VERSION 5.7 ;
  NOWIREEXTENSIONATPIN ON ;
  DIVIDERCHAR "/" ;
  BUSBITCHARS "[]" ;
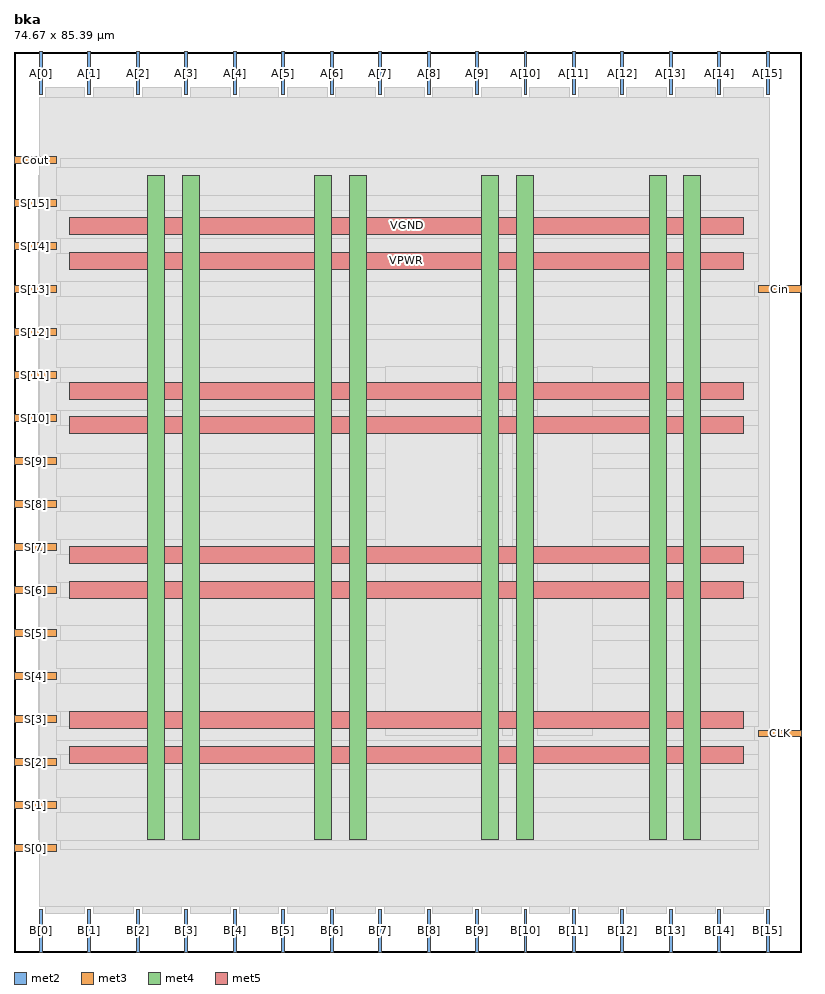
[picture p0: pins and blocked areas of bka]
MACRO bka
  CLASS BLOCK ;
  FOREIGN bka ;
  ORIGIN 0.000 0.000 ;
  SIZE 74.670 BY 85.390 ;
  PIN A[0]
    DIRECTION INPUT ;
    USE SIGNAL ;
    ANTENNAGATEAREA 0.196500 ;
    PORT
      LAYER met2 ;
        RECT 2.390 81.390 2.670 85.390 ;
    END
  END A[0]
  PIN A[10]
    DIRECTION INPUT ;
    USE SIGNAL ;
    ANTENNAGATEAREA 0.196500 ;
    PORT
      LAYER met2 ;
        RECT 48.390 81.390 48.670 85.390 ;
    END
  END A[10]
  PIN A[11]
    DIRECTION INPUT ;
    USE SIGNAL ;
    ANTENNAGATEAREA 0.196500 ;
    PORT
      LAYER met2 ;
        RECT 52.990 81.390 53.270 85.390 ;
    END
  END A[11]
  PIN A[12]
    DIRECTION INPUT ;
    USE SIGNAL ;
    ANTENNAGATEAREA 0.196500 ;
    PORT
      LAYER met2 ;
        RECT 57.590 81.390 57.870 85.390 ;
    END
  END A[12]
  PIN A[13]
    DIRECTION INPUT ;
    USE SIGNAL ;
    ANTENNAGATEAREA 0.196500 ;
    PORT
      LAYER met2 ;
        RECT 62.190 81.390 62.470 85.390 ;
    END
  END A[13]
  PIN A[14]
    DIRECTION INPUT ;
    USE SIGNAL ;
    ANTENNAGATEAREA 0.196500 ;
    PORT
      LAYER met2 ;
        RECT 66.790 81.390 67.070 85.390 ;
    END
  END A[14]
  PIN A[15]
    DIRECTION INPUT ;
    USE SIGNAL ;
    ANTENNAGATEAREA 0.196500 ;
    PORT
      LAYER met2 ;
        RECT 71.390 81.390 71.670 85.390 ;
    END
  END A[15]
  PIN A[1]
    DIRECTION INPUT ;
    USE SIGNAL ;
    ANTENNAGATEAREA 0.196500 ;
    PORT
      LAYER met2 ;
        RECT 6.990 81.390 7.270 85.390 ;
    END
  END A[1]
  PIN A[2]
    DIRECTION INPUT ;
    USE SIGNAL ;
    ANTENNAGATEAREA 0.196500 ;
    PORT
      LAYER met2 ;
        RECT 11.590 81.390 11.870 85.390 ;
    END
  END A[2]
  PIN A[3]
    DIRECTION INPUT ;
    USE SIGNAL ;
    ANTENNAGATEAREA 0.196500 ;
    PORT
      LAYER met2 ;
        RECT 16.190 81.390 16.470 85.390 ;
    END
  END A[3]
  PIN A[4]
    DIRECTION INPUT ;
    USE SIGNAL ;
    ANTENNAGATEAREA 0.196500 ;
    PORT
      LAYER met2 ;
        RECT 20.790 81.390 21.070 85.390 ;
    END
  END A[4]
  PIN A[5]
    DIRECTION INPUT ;
    USE SIGNAL ;
    ANTENNAGATEAREA 0.196500 ;
    PORT
      LAYER met2 ;
        RECT 25.390 81.390 25.670 85.390 ;
    END
  END A[5]
  PIN A[6]
    DIRECTION INPUT ;
    USE SIGNAL ;
    ANTENNAGATEAREA 0.196500 ;
    PORT
      LAYER met2 ;
        RECT 29.990 81.390 30.270 85.390 ;
    END
  END A[6]
  PIN A[7]
    DIRECTION INPUT ;
    USE SIGNAL ;
    ANTENNAGATEAREA 0.196500 ;
    PORT
      LAYER met2 ;
        RECT 34.590 81.390 34.870 85.390 ;
    END
  END A[7]
  PIN A[8]
    DIRECTION INPUT ;
    USE SIGNAL ;
    ANTENNAGATEAREA 0.196500 ;
    PORT
      LAYER met2 ;
        RECT 39.190 81.390 39.470 85.390 ;
    END
  END A[8]
  PIN A[9]
    DIRECTION INPUT ;
    USE SIGNAL ;
    ANTENNAGATEAREA 0.196500 ;
    PORT
      LAYER met2 ;
        RECT 43.790 81.390 44.070 85.390 ;
    END
  END A[9]
  PIN B[0]
    DIRECTION INPUT ;
    USE SIGNAL ;
    ANTENNAGATEAREA 0.196500 ;
    PORT
      LAYER met2 ;
        RECT 2.390 0.000 2.670 4.000 ;
    END
  END B[0]
  PIN B[10]
    DIRECTION INPUT ;
    USE SIGNAL ;
    ANTENNAGATEAREA 0.196500 ;
    PORT
      LAYER met2 ;
        RECT 48.390 0.000 48.670 4.000 ;
    END
  END B[10]
  PIN B[11]
    DIRECTION INPUT ;
    USE SIGNAL ;
    ANTENNAGATEAREA 0.196500 ;
    PORT
      LAYER met2 ;
        RECT 52.990 0.000 53.270 4.000 ;
    END
  END B[11]
  PIN B[12]
    DIRECTION INPUT ;
    USE SIGNAL ;
    ANTENNAGATEAREA 0.196500 ;
    PORT
      LAYER met2 ;
        RECT 57.590 0.000 57.870 4.000 ;
    END
  END B[12]
  PIN B[13]
    DIRECTION INPUT ;
    USE SIGNAL ;
    ANTENNAGATEAREA 0.196500 ;
    PORT
      LAYER met2 ;
        RECT 62.190 0.000 62.470 4.000 ;
    END
  END B[13]
  PIN B[14]
    DIRECTION INPUT ;
    USE SIGNAL ;
    ANTENNAGATEAREA 0.196500 ;
    PORT
      LAYER met2 ;
        RECT 66.790 0.000 67.070 4.000 ;
    END
  END B[14]
  PIN B[15]
    DIRECTION INPUT ;
    USE SIGNAL ;
    ANTENNAGATEAREA 0.196500 ;
    PORT
      LAYER met2 ;
        RECT 71.390 0.000 71.670 4.000 ;
    END
  END B[15]
  PIN B[1]
    DIRECTION INPUT ;
    USE SIGNAL ;
    ANTENNAGATEAREA 0.196500 ;
    PORT
      LAYER met2 ;
        RECT 6.990 0.000 7.270 4.000 ;
    END
  END B[1]
  PIN B[2]
    DIRECTION INPUT ;
    USE SIGNAL ;
    ANTENNAGATEAREA 0.196500 ;
    PORT
      LAYER met2 ;
        RECT 11.590 0.000 11.870 4.000 ;
    END
  END B[2]
  PIN B[3]
    DIRECTION INPUT ;
    USE SIGNAL ;
    ANTENNAGATEAREA 0.196500 ;
    PORT
      LAYER met2 ;
        RECT 16.190 0.000 16.470 4.000 ;
    END
  END B[3]
  PIN B[4]
    DIRECTION INPUT ;
    USE SIGNAL ;
    ANTENNAGATEAREA 0.196500 ;
    PORT
      LAYER met2 ;
        RECT 20.790 0.000 21.070 4.000 ;
    END
  END B[4]
  PIN B[5]
    DIRECTION INPUT ;
    USE SIGNAL ;
    ANTENNAGATEAREA 0.196500 ;
    PORT
      LAYER met2 ;
        RECT 25.390 0.000 25.670 4.000 ;
    END
  END B[5]
  PIN B[6]
    DIRECTION INPUT ;
    USE SIGNAL ;
    ANTENNAGATEAREA 0.196500 ;
    PORT
      LAYER met2 ;
        RECT 29.990 0.000 30.270 4.000 ;
    END
  END B[6]
  PIN B[7]
    DIRECTION INPUT ;
    USE SIGNAL ;
    ANTENNAGATEAREA 0.196500 ;
    PORT
      LAYER met2 ;
        RECT 34.590 0.000 34.870 4.000 ;
    END
  END B[7]
  PIN B[8]
    DIRECTION INPUT ;
    USE SIGNAL ;
    ANTENNAGATEAREA 0.196500 ;
    PORT
      LAYER met2 ;
        RECT 39.190 0.000 39.470 4.000 ;
    END
  END B[8]
  PIN B[9]
    DIRECTION INPUT ;
    USE SIGNAL ;
    ANTENNAGATEAREA 0.196500 ;
    PORT
      LAYER met2 ;
        RECT 43.790 0.000 44.070 4.000 ;
    END
  END B[9]
  PIN CLK
    DIRECTION INPUT ;
    USE SIGNAL ;
    ANTENNAGATEAREA 0.852000 ;
    PORT
      LAYER met3 ;
        RECT 70.670 20.440 74.670 21.040 ;
    END
  END CLK
  PIN Cin
    DIRECTION INPUT ;
    USE SIGNAL ;
    ANTENNAGATEAREA 0.196500 ;
    PORT
      LAYER met3 ;
        RECT 70.670 62.600 74.670 63.200 ;
    END
  END Cin
  PIN Cout
    DIRECTION OUTPUT ;
    USE SIGNAL ;
    ANTENNADIFFAREA 0.340600 ;
    PORT
      LAYER met3 ;
        RECT 0.000 74.840 4.000 75.440 ;
    END
  END Cout
  PIN S[0]
    DIRECTION OUTPUT ;
    USE SIGNAL ;
    ANTENNADIFFAREA 0.340600 ;
    PORT
      LAYER met3 ;
        RECT 0.000 9.560 4.000 10.160 ;
    END
  END S[0]
  PIN S[10]
    DIRECTION OUTPUT ;
    USE SIGNAL ;
    ANTENNADIFFAREA 0.340600 ;
    PORT
      LAYER met3 ;
        RECT 0.000 50.360 4.000 50.960 ;
    END
  END S[10]
  PIN S[11]
    DIRECTION OUTPUT ;
    USE SIGNAL ;
    ANTENNADIFFAREA 0.340600 ;
    PORT
      LAYER met3 ;
        RECT 0.000 54.440 4.000 55.040 ;
    END
  END S[11]
  PIN S[12]
    DIRECTION OUTPUT ;
    USE SIGNAL ;
    ANTENNADIFFAREA 0.340600 ;
    PORT
      LAYER met3 ;
        RECT 0.000 58.520 4.000 59.120 ;
    END
  END S[12]
  PIN S[13]
    DIRECTION OUTPUT ;
    USE SIGNAL ;
    ANTENNADIFFAREA 0.340600 ;
    PORT
      LAYER met3 ;
        RECT 0.000 62.600 4.000 63.200 ;
    END
  END S[13]
  PIN S[14]
    DIRECTION OUTPUT ;
    USE SIGNAL ;
    ANTENNADIFFAREA 0.340600 ;
    PORT
      LAYER met3 ;
        RECT 0.000 66.680 4.000 67.280 ;
    END
  END S[14]
  PIN S[15]
    DIRECTION OUTPUT ;
    USE SIGNAL ;
    ANTENNADIFFAREA 0.340600 ;
    PORT
      LAYER met3 ;
        RECT 0.000 70.760 4.000 71.360 ;
    END
  END S[15]
  PIN S[1]
    DIRECTION OUTPUT ;
    USE SIGNAL ;
    ANTENNADIFFAREA 0.340600 ;
    PORT
      LAYER met3 ;
        RECT 0.000 13.640 4.000 14.240 ;
    END
  END S[1]
  PIN S[2]
    DIRECTION OUTPUT ;
    USE SIGNAL ;
    ANTENNADIFFAREA 0.340600 ;
    PORT
      LAYER met3 ;
        RECT 0.000 17.720 4.000 18.320 ;
    END
  END S[2]
  PIN S[3]
    DIRECTION OUTPUT ;
    USE SIGNAL ;
    ANTENNADIFFAREA 0.340600 ;
    PORT
      LAYER met3 ;
        RECT 0.000 21.800 4.000 22.400 ;
    END
  END S[3]
  PIN S[4]
    DIRECTION OUTPUT ;
    USE SIGNAL ;
    ANTENNADIFFAREA 0.340600 ;
    PORT
      LAYER met3 ;
        RECT 0.000 25.880 4.000 26.480 ;
    END
  END S[4]
  PIN S[5]
    DIRECTION OUTPUT ;
    USE SIGNAL ;
    ANTENNADIFFAREA 0.340600 ;
    PORT
      LAYER met3 ;
        RECT 0.000 29.960 4.000 30.560 ;
    END
  END S[5]
  PIN S[6]
    DIRECTION OUTPUT ;
    USE SIGNAL ;
    ANTENNADIFFAREA 0.340600 ;
    PORT
      LAYER met3 ;
        RECT 0.000 34.040 4.000 34.640 ;
    END
  END S[6]
  PIN S[7]
    DIRECTION OUTPUT ;
    USE SIGNAL ;
    ANTENNADIFFAREA 0.340600 ;
    PORT
      LAYER met3 ;
        RECT 0.000 38.120 4.000 38.720 ;
    END
  END S[7]
  PIN S[8]
    DIRECTION OUTPUT ;
    USE SIGNAL ;
    ANTENNADIFFAREA 0.340600 ;
    PORT
      LAYER met3 ;
        RECT 0.000 42.200 4.000 42.800 ;
    END
  END S[8]
  PIN S[9]
    DIRECTION OUTPUT ;
    USE SIGNAL ;
    ANTENNADIFFAREA 0.340600 ;
    PORT
      LAYER met3 ;
        RECT 0.000 46.280 4.000 46.880 ;
    END
  END S[9]
  PIN VGND
    DIRECTION INOUT ;
    USE GROUND ;
    PORT
      LAYER met4 ;
        RECT 15.955 10.640 17.555 73.680 ;
    END
    PORT
      LAYER met4 ;
        RECT 31.825 10.640 33.425 73.680 ;
    END
    PORT
      LAYER met4 ;
        RECT 47.695 10.640 49.295 73.680 ;
    END
    PORT
      LAYER met4 ;
        RECT 63.565 10.640 65.165 73.680 ;
    END
    PORT
      LAYER met5 ;
        RECT 5.280 21.195 69.240 22.795 ;
    END
    PORT
      LAYER met5 ;
        RECT 5.280 36.830 69.240 38.430 ;
    END
    PORT
      LAYER met5 ;
        RECT 5.280 52.465 69.240 54.065 ;
    END
    PORT
      LAYER met5 ;
        RECT 5.280 68.100 69.240 69.700 ;
    END
  END VGND
  PIN VPWR
    DIRECTION INOUT ;
    USE POWER ;
    PORT
      LAYER met4 ;
        RECT 12.655 10.640 14.255 73.680 ;
    END
    PORT
      LAYER met4 ;
        RECT 28.525 10.640 30.125 73.680 ;
    END
    PORT
      LAYER met4 ;
        RECT 44.395 10.640 45.995 73.680 ;
    END
    PORT
      LAYER met4 ;
        RECT 60.265 10.640 61.865 73.680 ;
    END
    PORT
      LAYER met5 ;
        RECT 5.280 17.895 69.240 19.495 ;
    END
    PORT
      LAYER met5 ;
        RECT 5.280 33.530 69.240 35.130 ;
    END
    PORT
      LAYER met5 ;
        RECT 5.280 49.165 69.240 50.765 ;
    END
    PORT
      LAYER met5 ;
        RECT 5.280 64.800 69.240 66.400 ;
    END
  END VPWR
  OBS
      LAYER nwell ;
        RECT 5.330 10.795 69.190 73.630 ;
      LAYER li1 ;
        RECT 5.520 10.795 69.000 73.525 ;
      LAYER met1 ;
        RECT 2.370 10.640 71.690 73.680 ;
      LAYER met2 ;
        RECT 2.950 81.110 6.710 82.010 ;
        RECT 7.550 81.110 11.310 82.010 ;
        RECT 12.150 81.110 15.910 82.010 ;
        RECT 16.750 81.110 20.510 82.010 ;
        RECT 21.350 81.110 25.110 82.010 ;
        RECT 25.950 81.110 29.710 82.010 ;
        RECT 30.550 81.110 34.310 82.010 ;
        RECT 35.150 81.110 38.910 82.010 ;
        RECT 39.750 81.110 43.510 82.010 ;
        RECT 44.350 81.110 48.110 82.010 ;
        RECT 48.950 81.110 52.710 82.010 ;
        RECT 53.550 81.110 57.310 82.010 ;
        RECT 58.150 81.110 61.910 82.010 ;
        RECT 62.750 81.110 66.510 82.010 ;
        RECT 67.350 81.110 71.110 82.010 ;
        RECT 2.400 4.280 71.660 81.110 ;
        RECT 2.950 3.670 6.710 4.280 ;
        RECT 7.550 3.670 11.310 4.280 ;
        RECT 12.150 3.670 15.910 4.280 ;
        RECT 16.750 3.670 20.510 4.280 ;
        RECT 21.350 3.670 25.110 4.280 ;
        RECT 25.950 3.670 29.710 4.280 ;
        RECT 30.550 3.670 34.310 4.280 ;
        RECT 35.150 3.670 38.910 4.280 ;
        RECT 39.750 3.670 43.510 4.280 ;
        RECT 44.350 3.670 48.110 4.280 ;
        RECT 48.950 3.670 52.710 4.280 ;
        RECT 53.550 3.670 57.310 4.280 ;
        RECT 58.150 3.670 61.910 4.280 ;
        RECT 62.750 3.670 66.510 4.280 ;
        RECT 67.350 3.670 71.110 4.280 ;
      LAYER met3 ;
        RECT 4.400 74.440 70.670 75.305 ;
        RECT 3.990 71.760 70.670 74.440 ;
        RECT 4.400 70.360 70.670 71.760 ;
        RECT 3.990 67.680 70.670 70.360 ;
        RECT 4.400 66.280 70.670 67.680 ;
        RECT 3.990 63.600 70.670 66.280 ;
        RECT 4.400 62.200 70.270 63.600 ;
        RECT 3.990 59.520 70.670 62.200 ;
        RECT 4.400 58.120 70.670 59.520 ;
        RECT 3.990 55.440 70.670 58.120 ;
        RECT 4.400 54.040 70.670 55.440 ;
        RECT 3.990 51.360 70.670 54.040 ;
        RECT 4.400 49.960 70.670 51.360 ;
        RECT 3.990 47.280 70.670 49.960 ;
        RECT 4.400 45.880 70.670 47.280 ;
        RECT 3.990 43.200 70.670 45.880 ;
        RECT 4.400 41.800 70.670 43.200 ;
        RECT 3.990 39.120 70.670 41.800 ;
        RECT 4.400 37.720 70.670 39.120 ;
        RECT 3.990 35.040 70.670 37.720 ;
        RECT 4.400 33.640 70.670 35.040 ;
        RECT 3.990 30.960 70.670 33.640 ;
        RECT 4.400 29.560 70.670 30.960 ;
        RECT 3.990 26.880 70.670 29.560 ;
        RECT 4.400 25.480 70.670 26.880 ;
        RECT 3.990 22.800 70.670 25.480 ;
        RECT 4.400 21.440 70.670 22.800 ;
        RECT 4.400 21.400 70.270 21.440 ;
        RECT 3.990 20.040 70.270 21.400 ;
        RECT 3.990 18.720 70.670 20.040 ;
        RECT 4.400 17.320 70.670 18.720 ;
        RECT 3.990 14.640 70.670 17.320 ;
        RECT 4.400 13.240 70.670 14.640 ;
        RECT 3.990 10.560 70.670 13.240 ;
        RECT 4.400 9.695 70.670 10.560 ;
      LAYER met4 ;
        RECT 35.255 20.575 43.995 55.585 ;
        RECT 46.395 20.575 47.295 55.585 ;
        RECT 49.695 20.575 54.905 55.585 ;
  END
END bka
END LIBRARY

